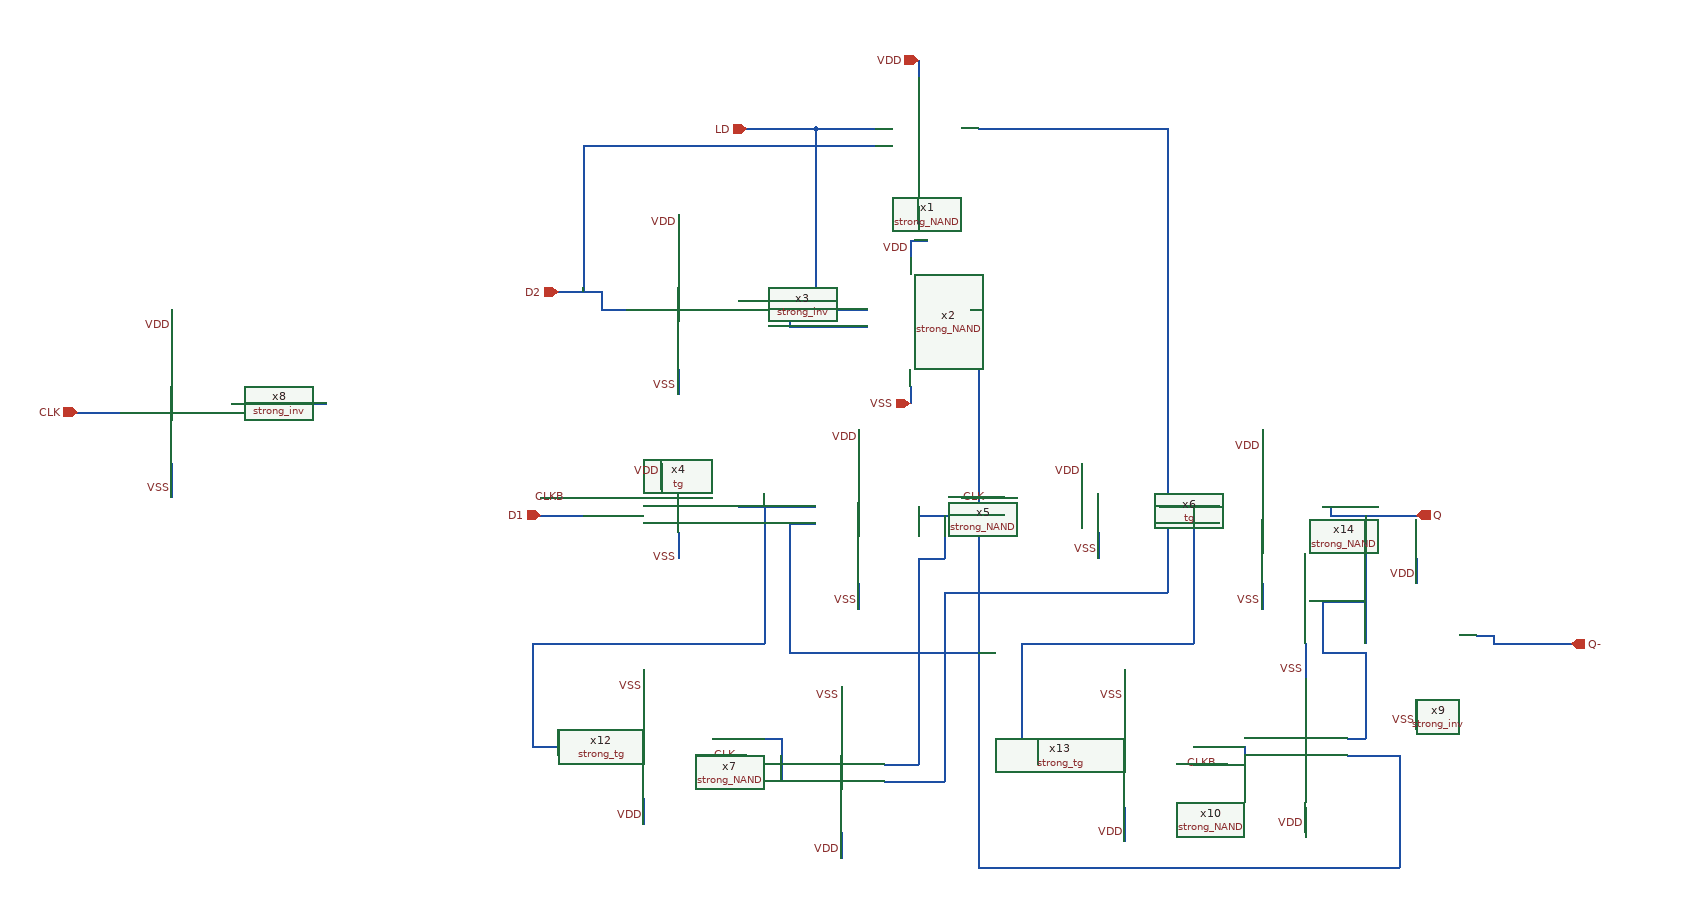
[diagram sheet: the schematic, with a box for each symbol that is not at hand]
v {xschem version=3.1.0 file_version=1.2
}
G {}
K {}
V {}
S {}
E {}
N -600 -780 -510 -780 {
lab=#net1}
N -570 -1010 -510 -1010 {
lab=LD}
N -840 -990 -840 -820 {
lab=D2}
N -840 -990 -510 -990 {
lab=D2}
N -650 -1010 -570 -1010 {
lab=LD}
N -730 -910 -730 -880 {
lab=VDD}
N -450 -920 -450 -900 {
lab=VSS}
N -460 -880 -460 -860 {
lab=VDD}
N -460 -880 -440 -880 {
lab=VDD}
N -460 -710 -460 -690 {
lab=VSS}
N -730 -730 -730 -700 {
lab=VSS}
N -890 -560 -840 -560 {
lab=D1}
N -890 -580 -840 -580 {
lab=CLKB}
N -750 -620 -750 -590 {
lab=VDD}
N -730 -540 -730 -510 {
lab=VSS}
N -660 -570 -570 -570 {
lab=#net2}
N -440 -560 -350 -560 {
lab=#net3}
N -170 -570 -100 -570 {
lab=#net4}
N 30 -560 90 -560 {
lab=Q}
N 70 -560 70 -420 {
lab=Q}
N 90 -560 130 -560 {
lab=Q}
N 260 -410 310 -410 {
lab=Q-}
N -520 -660 -520 -630 {
lab=VDD}
N -260 -620 -260 -590 {
lab=VDD}
N -240 -540 -240 -510 {
lab=VSS}
N -50 -660 -50 -630 {
lab=VDD}
N -50 -480 -50 -450 {
lab=VSS}
N 130 -510 130 -480 {
lab=VDD}
N 130 -340 130 -310 {
lab=VSS}
N 20 -460 70 -460 {
lab=Q}
N -380 -150 30 -150 {
lab=#net5}
N 30 -150 110 -150 {
lab=#net5}
N 110 -280 110 -150 {
lab=#net5}
N 50 -280 110 -280 {
lab=#net5}
N 20 -460 20 -400 {
lab=Q}
N 20 -400 70 -400 {
lab=Q}
N 70 -400 70 -300 {
lab=Q}
N 50 -300 70 -300 {
lab=Q}
N -380 -1010 -170 -1010 {
lab=#net6}
N -160 -1000 -160 -550 {
lab=#net6}
N -160 -550 -100 -550 {
lab=#net6}
N -130 -290 -80 -290 {
lab=#net7}
N -330 -280 -310 -280 {
lab=#net4}
N -330 -410 -330 -280 {
lab=#net4}
N -330 -410 -130 -410 {
lab=#net4}
N -130 -570 -130 -410 {
lab=#net4}
N -160 -550 -160 -470 {
lab=#net6}
N -420 -470 -160 -470 {
lab=#net6}
N -420 -470 -420 -290 {
lab=#net6}
N -490 -250 -420 -250 {
lab=#net6}
N -420 -560 -420 -510 {
lab=#net3}
N -450 -510 -420 -510 {
lab=#net3}
N -450 -510 -450 -310 {
lab=#net3}
N -490 -270 -450 -270 {
lab=#net3}
N -690 -300 -620 -300 {
lab=#net8}
N -900 -290 -870 -290 {
lab=#net2}
N -900 -410 -900 -290 {
lab=#net2}
N -900 -410 -630 -410 {
lab=#net2}
N -630 -570 -630 -410 {
lab=#net2}
N -600 -400 -380 -400 {
lab=#net5}
N -600 -550 -600 -400 {
lab=#net5}
N -600 -550 -570 -550 {
lab=#net5}
N -770 -380 -770 -350 {
lab=VSS}
N -770 -230 -770 -200 {
lab=VDD}
N -540 -360 -540 -340 {
lab=VSS}
N -540 -190 -540 -160 {
lab=VDD}
N 0 -410 0 -370 {
lab=VSS}
N 0 -220 0 -190 {
lab=VDD}
N -1430 -680 -1380 -680 {
lab=CLK}
N -1190 -690 -1140 -690 {
lab=CLKB}
N -1320 -800 -1320 -760 {
lab=VDD}
N -1320 -620 -1320 -580 {
lab=VSS}
N -690 -280 -650 -280 {
lab=CLK}
N -400 -580 -350 -580 {
lab=CLK}
N -130 -270 -90 -270 {
lab=CLKB}
N -570 -1010 -570 -830 {
lab=LD}
N -1250 -690 -1190 -690 {
lab=CLKB}
N -870 -820 -820 -820 {
lab=D2}
N -820 -820 -820 -800 {
lab=D2}
N -820 -800 -790 -800 {
lab=D2}
N -660 -810 -600 -810 {
lab=#net1}
N 70 -420 70 -410 {
lab=Q}
N 200 -420 220 -420 {
lab=Q-}
N 220 -420 220 -410 {
lab=Q-}
N 220 -410 260 -410 {
lab=Q-}
N -510 -990 -500 -990 {
lab=D2}
N -510 -1010 -500 -1010 {
lab=LD}
N -450 -1090 -450 -1070 {
lab=VDD}
N -160 -1010 -160 -1000 {
lab=#net6}
N -170 -1010 -160 -1010 {
lab=#net6}
N -600 -810 -600 -780 {
lab=#net1}
N -570 -830 -570 -810 {
lab=LD}
N -570 -810 -570 -800 {
lab=LD}
N -570 -800 -510 -800 {
lab=LD}
N -390 -800 -380 -800 {
lab=#net5}
N -380 -800 -380 -150 {
lab=#net5}
N -520 -480 -520 -450 {
lab=VSS}
N -450 -570 -450 -560 {
lab=#net3}
N -450 -560 -440 -560 {
lab=#net3}
N 20 -570 30 -570 {
lab=Q}
N 30 -570 30 -560 {
lab=Q}
N -420 -290 -420 -250 {
lab=#net6}
N -450 -310 -450 -270 {
lab=#net3}
N -610 -300 -610 -250 {
lab=#net8}
N -620 -300 -610 -300 {
lab=#net8}
N -70 -290 -70 -280 {
lab=#net7}
N -80 -290 -70 -290 {
lab=#net7}
N -870 -290 -870 -280 {
lab=#net2}
N -210 -380 -210 -340 {
lab=VSS}
N -210 -220 -210 -180 {
lab=VDD}
N -310 -280 -310 -270 {}
C {devices/ipin.sym} -650 -1010 0 0 {name=p1 lab=LD}
C {devices/ipin.sym} -870 -820 0 0 {name=p2 lab=D2}
C {devices/iopin.sym} -450 -1090 3 0 {name=p3 lab=VDD}
C {devices/iopin.sym} -460 -690 1 0 {name=p4 lab=VSS}
C {devices/lab_wire.sym} -730 -900 0 0 {name=p5 sig_type=std_logic lab=VDD}
C {devices/lab_wire.sym} -730 -710 0 0 {name=p6 sig_type=std_logic lab=VSS}
C {devices/lab_wire.sym} -460 -870 0 0 {name=p7 sig_type=std_logic lab=VDD}
C {devices/lab_wire.sym} -450 -910 0 0 {name=p8 sig_type=std_logic lab=VSS}
C {tg.sym} -690 -560 0 0 {name=x4}
C {devices/ipin.sym} -890 -560 0 0 {name=p9 lab=D1}
C {devices/lab_wire.sym} -750 -610 0 0 {name=p10 sig_type=std_logic lab=VDD}
C {devices/lab_wire.sym} -730 -510 0 0 {name=p11 sig_type=std_logic lab=VSS}
C {tg.sym} -200 -560 0 0 {name=x6}
C {devices/opin.sym} 130 -560 0 0 {name=p12 lab=Q}
C {devices/opin.sym} 310 -410 0 0 {name=p13 lab=Q-}
C {devices/lab_wire.sym} -520 -650 0 0 {name=p14 sig_type=std_logic lab=VDD}
C {devices/lab_wire.sym} -260 -610 0 0 {name=p15 sig_type=std_logic lab=VDD}
C {devices/lab_wire.sym} -50 -640 0 0 {name=p16 sig_type=std_logic lab=VDD}
C {devices/lab_wire.sym} 130 -490 0 0 {name=p17 sig_type=std_logic lab=VDD}
C {devices/lab_wire.sym} -770 -210 0 0 {name=p18 sig_type=std_logic lab=VDD}
C {devices/lab_wire.sym} -540 -170 0 0 {name=p19 sig_type=std_logic lab=VDD}
C {devices/lab_wire.sym} 0 -200 0 0 {name=p21 sig_type=std_logic lab=VDD}
C {devices/lab_wire.sym} -240 -520 0 0 {name=p23 sig_type=std_logic lab=VSS}
C {devices/lab_wire.sym} -50 -460 0 0 {name=p24 sig_type=std_logic lab=VSS}
C {devices/lab_wire.sym} 130 -320 0 0 {name=p25 sig_type=std_logic lab=VSS}
C {devices/lab_wire.sym} 0 -380 0 0 {name=p26 sig_type=std_logic lab=VSS}
C {devices/lab_wire.sym} -540 -350 0 0 {name=p28 sig_type=std_logic lab=VSS}
C {devices/lab_wire.sym} -770 -360 0 0 {name=p29 sig_type=std_logic lab=VSS}
C {devices/lab_wire.sym} -1320 -590 0 0 {name=p30 sig_type=std_logic lab=VSS}
C {devices/lab_wire.sym} -1320 -780 0 0 {name=p31 sig_type=std_logic lab=VDD}
C {devices/ipin.sym} -1430 -680 0 0 {name=p32 lab=CLK}
C {devices/lab_wire.sym} -1150 -690 0 0 {name=p33 sig_type=std_logic lab=CLKB}
C {devices/lab_wire.sym} -1150 -690 0 0 {name=p34 sig_type=std_logic lab=CLKB}
C {devices/lab_wire.sym} -860 -580 0 0 {name=p35 sig_type=std_logic lab=CLKB}
C {devices/lab_wire.sym} -100 -270 0 0 {name=p36 sig_type=std_logic lab=CLKB}
C {devices/lab_wire.sym} -370 -580 0 0 {name=p37 sig_type=std_logic lab=CLK}
C {devices/lab_wire.sym} -660 -280 0 0 {name=p38 sig_type=std_logic lab=CLK}
C {strong_inv.sym} -640 -780 0 0 {name=x3}
C {strong_inv.sym} -1230 -660 0 0 {name=x8}
C {strong_inv.sym} 220 -390 0 0 {name=x9}
C {strong_NAND.sym} 50 -550 0 0 {name=x14}
C {strong_NAND.sym} -350 -990 0 0 {name=x1}
C {strong_NAND.sym} -360 -780 0 0 {name=x2}
C {strong_NAND.sym} -420 -550 0 0 {name=x5}
C {devices/lab_wire.sym} -520 -460 0 0 {name=p39 sig_type=std_logic lab=VSS}
C {strong_NAND.sym} -640 -270 2 0 {name=x7}
C {strong_NAND.sym} -100 -300 2 0 {name=x10}
C {strong_tg.sym} -840 -300 2 0 {name=x12}
C {devices/lab_wire.sym} -210 -190 0 0 {name=p22 sig_type=std_logic lab=VDD}
C {devices/lab_wire.sym} -210 -350 0 0 {name=p40 sig_type=std_logic lab=VSS}
C {strong_tg.sym} -280 -290 2 0 {name=x13}
